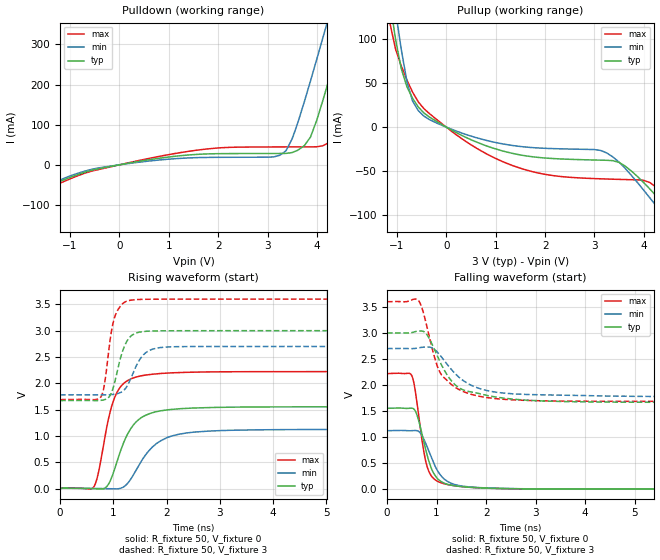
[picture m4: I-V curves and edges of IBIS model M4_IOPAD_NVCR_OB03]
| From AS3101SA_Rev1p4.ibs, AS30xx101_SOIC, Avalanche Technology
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[Model] M4_IOPAD_NVCR_OB03
Model_type Output
Enable   Active-High
Vmeas =  1.5
Cref  =  30e-12
| Capacitance  typ   min   max
C_comp   0   0   0
| Variables   typ   min   max
[GND Clamp Reference]   0   0   0
[POWER Clamp Reference]   3   2.7   3.6
[Pulldown Reference]   0   0   0
[Pullup Reference]   3   2.7   3.6
[Temperature Range]   25   105   -40
[Voltage Range]   3   2.7   3.6
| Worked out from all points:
|   slope of the pulldown table from 0 to 0.45 V, typ, clamps not added: 46 ohm
|   slope of the pullup table from 0 to 0.45 V, typ, clamps not added: 34.5 ohm
|   falling waveform, R_fixture 50, V_fixture 0: 20-80 % time 279ps typ, 349ps min, 219ps max; typ from 1.55 V to 0 V
|   falling waveform, R_fixture 50, V_fixture 3: 20-80 % time 543ps typ, 663ps min, 453ps max; typ from 3 V to 1.67 V
|   rising waveform, R_fixture 50, V_fixture 0: 20-80 % time 402ps typ, 521ps min, 297ps max; typ from 0 V to 1.55 V
|   rising waveform, R_fixture 50, V_fixture 3: 20-80 % time 219ps typ, 276ps min, 166ps max; typ from 1.67 V to 3 V
[Pulldown]
| Voltage   I(typ)   I(min)   I(max)
-3V       -147.2mA   -153mA     -147.4mA
-569mV    -13.77mA   -11.43mA   -15.98mA
1.552V    25.86mA    17.87mA    36.21mA
3.248V    28.34mA    23.9mA     44.61mA
3.497V    30.56mA    64.65mA    44.69mA
3.745V    47.87mA    157.8mA    44.76mA
4.117V    159.8mA    315.8mA    47.45mA
4.49V     320.1mA    478.8mA    82.88mA
4.614V    374.8mA    533.5mA    109.5mA
5.11V     595.6mA    752.8mA    317.1mA
5.234V    650.8mA    807.7mA    372.5mA
6V        991mA      1.147A     716.8mA
[Pullup]
| Voltage   I(typ)   I(min)   I(max)
-3V       950.3mA    984.6mA    924mA
-1.138V   140.9mA    176.2mA    117.3mA
-1.024V   98.82mA    130.9mA    88.09mA
-910.3mV  66.24mA    87.97mA    69.46mA
-682.8mV  32.88mA    29.71mA    39.81mA
-341.4mV  11.45mA    8.577mA    15.37mA
1.345V    -29.89mA   -20.89mA   -43.75mA
3.124V    -37.56mA   -26.51mA   -58.79mA
4.117V    -70.13mA   -80.15mA   -62.94mA
4.614V    -102.6mA   -115.7mA   -90.27mA
4.986V    -129.5mA   -142.9mA   -116mA
6V        -205.8mA   -218.4mA   -188.3mA
[Ramp]
dV/dt_r   0.931955/0.401817n  0.673943/0.520651n  1.33324/0.296908n
dV/dt_f   0.799473/0.543284n  0.553656/0.663318n  1.14844/0.452872n
R_load = 50
[Falling Waveform]
R_fixture = 50
V_fixture = 0
V_fixture_min = 0
V_fixture_max = 0
| Time   V(typ)   V(min)   V(max)
0s        1.553V     1.123V     2.222V
495.5ps   1.556V     1.123V     2.189V
543ps     1.539V     1.126V     2.038V
615.3ps   1.394V     1.121V     1.583V
731.8ps   952.6mV    982.6mV    780.2mV
838.4ps   555.3mV    741.3mV    354.5mV
949.5ps   291.5mV    484.3mV    196.4mV
1.101ns   140.7mV    243.8mV    118.6mV
1.489ns   50.53mV    63.13mV    50.77mV
21.88ns   478.9nV    595.3nV    10.18uV
[Falling Waveform]
R_fixture = 50
V_fixture = 3
V_fixture_min = 2.7
V_fixture_max = 3.6
| Time   V(typ)   V(min)   V(max)
0s        3V         2.7V       3.6V
625.8ps   3.037V     2.712V     3.633V
699.1ps   3.039V     2.724V     3.498V
813.3ps   2.956V     2.731V     3.087V
978.9ps   2.635V     2.668V     2.466V
1.092ns   2.4V       2.547V     2.205V
1.459ns   1.943V     2.145V     1.911V
2.195ns   1.77V      1.864V     1.738V
4.389ns   1.672V     1.79V      1.687V
21.88ns   1.668V     1.777V     1.686V
[Rising Waveform]
R_fixture = 50
V_fixture = 0
V_fixture_min = 0
V_fixture_max = 0
| Time   V(typ)   V(min)   V(max)
0s        382nV      443.2nV    10.07uV
614.8ps   -1.423mV   3.059mV    9.209mV
711ps     -7.837mV   1.293mV    263.7mV
872.8ps   33.79mV    -3.33mV    1.152V
1.07ns    516.4mV    -7.116mV   1.829V
1.361ns   1.187V     233.3mV    2.096V
1.693ns   1.428V     746.7mV    2.168V
2.226ns   1.515V     1.03V      2.203V
3.482ns   1.548V     1.112V     2.22V
21.88ns   1.553V     1.123V     2.222V
[Rising Waveform]
R_fixture = 50
V_fixture = 3
V_fixture_min = 2.7
V_fixture_max = 3.6
| Time   V(typ)   V(min)   V(max)
0s        1.668V     1.777V     1.686V
767.9ps   1.675V     1.779V     1.744V
837.4ps   1.689V     1.779V     2.007V
933.6ps   1.761V     1.783V     2.787V
1.032ns   2.045V     1.794V     3.278V
1.196ns   2.673V     1.865V     3.53V
1.389ns   2.938V     2.237V     3.587V
1.655ns   2.991V     2.612V     3.596V
2.199ns   2.998V     2.696V     3.599V
21.88ns   3V         2.7V       3.6V
